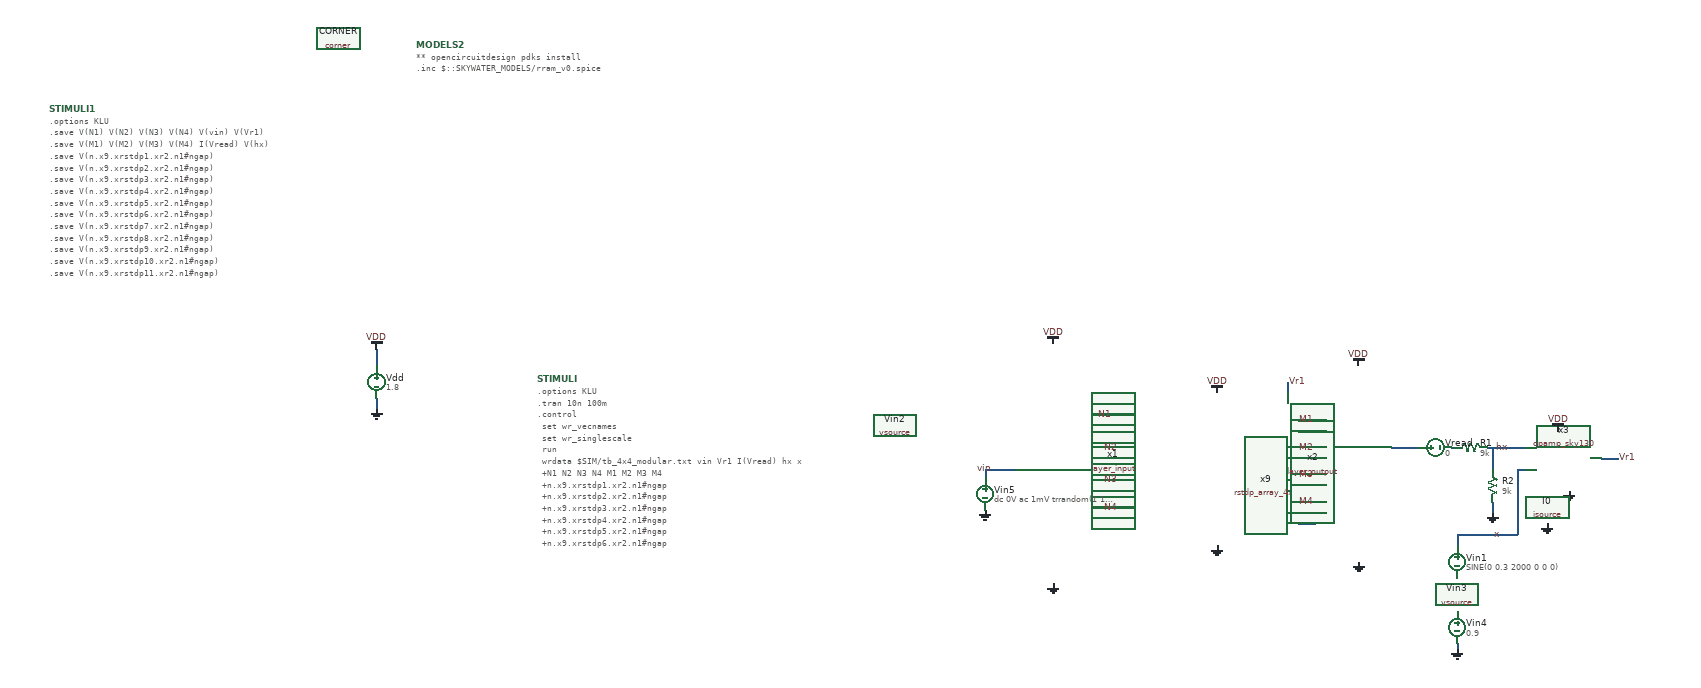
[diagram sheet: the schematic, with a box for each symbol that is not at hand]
v {xschem version=3.4.5 file_version=1.2
}
G {}
K {}
V {}
S {}
E {}
B 2 -840 -1020 -40 -620 {flags=graph
y1=1.2	
y2=6.8
ypos1=-0.00012
ypos2=3.7
divy=5
subdivy=1
unity=1
x1=0
x2=1e-06
divx=5
subdivx=1


dataset=-1
unitx=1
logx=0
logy=0
digital=0
linewidth_mult=3.5
color="6 8 4 7"
node="\\"N1; n1 1.8 3 * +\\"
\\"N2; n2 1.8 2 * +\\"
\\"N3; n3 1.8 +\\"
\\"N4; n4\\""}
B 2 -840 -1430 -40 -1030 {flags=graph
y1=1.3	
y2=1.5
ypos1=-0.319016
ypos2=2.49867
divy=5
subdivy=1
unity=1
x1=0
x2=1e-06
divx=5
subdivx=1


dataset=-1
unitx=1
logx=0
logy=0
digital=0
linewidth_mult=3.5
color=6
node=vin}
B 2 840 -1020 1640 -620 {flags=graph
y1=-0.005	
y2=7.3
ypos1=-0.00012
ypos2=3.7
divy=5
subdivy=1
unity=1
x1=0
x2=1e-06
divx=5
subdivx=1


dataset=-1
unitx=1
logx=0
logy=0
digital=0
linewidth_mult=3.5
color="6 8 4 7"
node="\\"N1; m1 5.4 +\\"
\\"N2; m2 3.6 +\\"
\\"N3; m3 1.8 +\\"
\\"N4; m4\\""}
B 2 0 -1015 800 -615 {flags=graph
y1=0.0028	
y2=1.9
ypos1=-0.00012
ypos2=3.7
divy=5
subdivy=1
unity=1
x1=0
x2=1e-06
divx=5
subdivx=1


dataset=-1
unitx=1
logx=0
logy=0
digital=0
linewidth_mult=3.5

color="4 5"
node="vr1
hx"}
B 2 0 -1430 800 -1030 {flags=graph
y1=1.6	
y2=4.6
ypos1=-0.00012
ypos2=3.7
divy=5
subdivy=1
unity=1
x1=0
x2=1e-06
divx=5
subdivx=1


dataset=-1
unitx=1
logx=0
logy=0
digital=0
linewidth_mult=3.5

color="4 5 6 7 8 9 10 11 12 13 14 15 16 17 18 19"
node="\\"Mem16; 5 n.x9.xrstdp16.xr2.n1#ngap - \\"
\\"Mem15; 5 n.x9.xrstdp15.xr2.n1#ngap - \\"
\\"Mem14; 5 n.x9.xrstdp14.xr2.n1#ngap - \\"
\\"Mem13; 5 n.x9.xrstdp13.xr2.n1#ngap - \\"
\\"Mem12; 5 n.x9.xrstdp12.xr2.n1#ngap - \\"
\\"Mem11; 5 n.x9.xrstdp11.xr2.n1#ngap - \\"
\\"Mem10; 5 n.x9.xrstdp10.xr2.n1#ngap - \\"
\\"Mem9; 5 n.x9.xrstdp9.xr2.n1#ngap - \\"
\\"Mem8; 5 n.x9.xrstdp8.xr2.n1#ngap - \\"
\\"Mem7; 5 n.x9.xrstdp7.xr2.n1#ngap - \\"
\\"Mem6; 5 n.x9.xrstdp6.xr2.n1#ngap - \\"
\\"Mem5; 5 n.x9.xrstdp5.xr2.n1#ngap - \\"
\\"Mem4; 5 n.x9.xrstdp4.xr2.n1#ngap - \\"
\\"Mem3; 5 n.x9.xrstdp3.xr2.n1#ngap - \\"
\\"Mem2; 5 n.x9.xrstdp2.xr2.n1#ngap - \\"
\\"Mem1; 5 n.x9.xrstdp1.xr2.n1#ngap - \\""}
B 2 840 -1430 1640 -1030 {flags=graph
y1=7.5e-07	
y2=4.3e-05
ypos1=-0.00012
ypos2=3.7
divy=5
subdivy=1
unity=1
x1=0
x2=1e-06
divx=5
subdivx=1


dataset=-1
unitx=1
logx=0
logy=0
digital=0
linewidth_mult=3.5

color=4
node=i(Vread)}
N -1120 -520 -1120 -490 {
lab=VDD}
N -1120 -430 -1120 -410 {
lab=GND}
N 860 -180 860 -160 {
lab=x}
N 860 -180 970 -180 {
lab=x}
N 240 -400 270 -400 {
lab=N1}
N 240 -230 270 -230 {
lab=N4}
N 740 -340 790 -340 {
lab=#net1}
N 220 -400 240 -400 {
lab=N1}
N 190 -250 220 -250 {
lab=N4}
N 220 -230 240 -230 {
lab=N4}
N 230 -340 270 -340 {
lab=N2}
N 190 -310 230 -310 {
lab=N3}
N 230 -300 230 -280 {
lab=N3}
N 230 -280 270 -280 {
lab=N3}
N 570 -340 620 -340 {
lab=M2}
N 570 -320 620 -320 {
lab=#net2}
N 570 -280 590 -280 {
lab=M3}
N 590 -290 590 -280 {
lab=M3}
N 590 -290 620 -290 {
lab=M3}
N 600 -270 620 -270 {
lab=#net3}
N 600 -270 600 -260 {
lab=#net3}
N 570 -260 600 -260 {
lab=#net3}
N 570 -220 580 -220 {
lab=M4}
N 580 -240 580 -220 {
lab=M4}
N 580 -240 620 -240 {
lab=M4}
N 570 -200 600 -200 {
lab=#net4}
N 600 -220 600 -200 {
lab=#net4}
N 600 -220 620 -220 {
lab=#net4}
N 570 -370 620 -370 {
lab=#net5}
N 570 -390 620 -390 {
lab=M1}
N 220 -420 220 -400 {
lab=N1}
N 190 -420 220 -420 {
lab=N1}
N 230 -370 230 -340 {
lab=N2}
N 190 -370 230 -370 {
lab=N2}
N 230 -310 230 -300 {
lab=N3}
N 220 -250 220 -230 {
lab=N4}
N 915 -340 945 -340 {
lab=hx}
N 955 -340 985 -340 {
lab=hx}
N 945 -340 955 -340 {
lab=hx}
N 925 -240 925 -220 {
lab=GND}
N 925 -340 925 -300 {
lab=hx}
N 1125 -320 1155 -320 {
lab=Vr1}
N 550 -460 550 -440 {
lab=Vr1}
N 850 -340 855 -340 {
lab=#net6}
N 190 -400 270 -380 {
lab=#net7}
N 190 -350 270 -320 {
lab=#net8}
N 190 -290 270 -260 {
lab=#net9}
N 190 -230 270 -210 {
lab=#net10}
N 860 20 860 30 {
lab=GND}
N 970 -300 970 -255 {
lab=x}
N 970 -300 985 -300 {
lab=x}
N 970 -255 970 -180 {
lab=x}
N -5 -300 -5 -285 {
lab=vin}
N -5 -300 50 -300 {
lab=vin}
C {devices/vsource.sym} -1120 -460 0 0 {name=Vdd value=1.8}
C {devices/gnd.sym} -1120 -410 0 0 {name=l5 lab=GND}
C {sky130_fd_pr/corner.sym} -1190 -1090 0 0 {name=CORNER only_toplevel=true corner=tt}
C {devices/code_shown.sym} -825 -465 0 0 {name=STIMULI 
only_toplevel=true
place=end
value="


.options KLU
.tran 10n 100m
.control
	set wr_vecnames
	set wr_singlescale
	run
	wrdata $SIM/tb_4x4_modular.txt vin Vr1 I(Vread) hx x
	+N1 N2 N3 N4 M1 M2 M3 M4  
	+n.x9.xrstdp1.xr2.n1#ngap 
	+n.x9.xrstdp2.xr2.n1#ngap 
	+n.x9.xrstdp3.xr2.n1#ngap
	+n.x9.xrstdp4.xr2.n1#ngap 
	+n.x9.xrstdp5.xr2.n1#ngap 
	+n.x9.xrstdp6.xr2.n1#ngap
	+n.x9.xrstdp7.xr2.n1#ngap 
	+n.x9.xrstdp8.xr2.n1#ngap 
	+n.x9.xrstdp9.xr2.n1#ngap
	+n.x9.xrstdp10.xr2.n1#ngap 
	+n.x9.xrstdp11.xr2.n1#ngap 
	+n.x9.xrstdp12.xr2.n1#ngap
	+n.x9.xrstdp13.xr2.n1#ngap 
	+n.x9.xrstdp14.xr2.n1#ngap 
	+n.x9.xrstdp15.xr2.n1#ngap
.endc
"}
C {devices/vdd.sym} -1120 -520 0 0 {nname=l4 lab=VDD}
C {devices/launcher.sym} -1095 -665 0 0 {name=h5
descr="load waves" 
tclcommand="xschem raw_read $netlist_dir/tb_4x4_modular.raw tran"
q}
C {devices/gnd.sym} 860 30 0 0 {name=l18 lab=GND}
C {Synapse/rstdp_array_4x4.sym} 420 -230 0 0 {name=x9}
C {devices/gnd.sym} 420 -160 0 0 {name=l30 lab=GND}
C {devices/vdd.sym} 420 -440 0 0 {name=l31 lab=VDD}
C {devices/code.sym} -1047.5 -1077.5 0 0 {name=MODELS2
only_toplevel=true
format="tcleval( @value )"
value="
** opencircuitdesign pdks install
.inc $::SKYWATER_MODELS/rram_v0.spice
"
spice_ignore=false}
C {layer/layer_input.sym} 130 -250 0 0 {name=x1}
C {layer/layer_output.sym} 770 -340 0 0 {name=x2}
C {devices/vdd.sym} 680 -490 0 0 {name=l6 lab=VDD}
C {devices/gnd.sym} 680 -130 0 0 {name=l7 lab=GND}
C {devices/gnd.sym} 120 -90 0 0 {name=l8 lab=GND}
C {devices/lab_pin.sym} 230 -400 1 0 {name=p2 sig_type=std_logic lab=N1}
C {devices/lab_pin.sym} 240 -340 1 0 {name=p3 sig_type=std_logic lab=N2}
C {devices/lab_pin.sym} 240 -280 1 0 {name=p4 sig_type=std_logic lab=N3}
C {devices/lab_pin.sym} 240 -230 1 0 {name=p5 sig_type=std_logic lab=N4}
C {devices/lab_pin.sym} 600 -390 1 0 {name=p6 sig_type=std_logic lab=M1}
C {devices/lab_pin.sym} 600 -340 1 0 {name=p7 sig_type=std_logic lab=M2}
C {devices/lab_pin.sym} 600 -290 1 0 {name=p8 sig_type=std_logic lab=M3}
C {devices/lab_pin.sym} 600 -240 1 0 {name=p9 sig_type=std_logic lab=M4}
C {devices/vdd.sym} 120 -530 0 0 {name=l9 lab=VDD}
C {OPAMP/opamp_sky130.sym} 1055 -320 0 0 {name=x3}
C {devices/lab_pin.sym} 955 -340 1 1 {name=p10 sig_type=std_logic lab=hx}
C {devices/res.sym} 885 -340 3 0 {name=R1
value=9k
footprint=1206
device=resistor
m=1}
C {devices/res.sym} 925 -270 0 0 {name=R2
value=9k
footprint=1206
device=resistor
m=1}
C {devices/gnd.sym} 925 -220 0 0 {name=l16 lab=GND}
C {devices/gnd.sym} 1065 -260 0 0 {name=l10 lab=GND}
C {devices/vdd.sym} 1045 -370 0 0 {name=l19 lab=VDD}
C {devices/lab_pin.sym} 940 -180 1 1 {name=p12 sig_type=std_logic lab=x
}
C {devices/lab_pin.sym} 1155 -320 2 0 {name=p11 sig_type=std_logic lab=Vr1
}
C {devices/isource.sym} 1025 -230 0 0 {name=I0 value=100u}
C {devices/gnd.sym} 1025 -200 0 0 {name=l13 lab=GND}
C {devices/vsource.sym} 860 -130 0 1 {name=Vin1 value="SINE(0 0.3 2000 0 0 0)"
spice_ignore=false}
C {devices/vsource.sym} 820 -340 3 1 {name=Vread value=0
spice_ignore=false}
C {devices/vsource.sym} -170 -380 0 1 {name=Vin2 value="PWL(0 0.9 250u 1.8 750u 0 1000u 0.9)"
spice_ignore=true}
C {devices/vsource.sym} 860 -70 0 1 {name=Vin3 value="SINE(0 0.5 5000 0 0 90)"
spice_ignore=false}
C {devices/vsource.sym} 860 -10 0 1 {name=Vin4 value=0.9
spice_ignore=false}
C {devices/code_shown.sym} -1720 -960 0 0 {name=STIMULI1 
only_toplevel=true
place=end
value="
.options KLU
.save V(N1) V(N2) V(N3) V(N4) V(vin) V(Vr1)
.save V(M1) V(M2) V(M3) V(M4) I(Vread) V(hx)
.save V(n.x9.xrstdp1.xr2.n1#ngap)
.save V(n.x9.xrstdp2.xr2.n1#ngap)
.save V(n.x9.xrstdp3.xr2.n1#ngap)
.save V(n.x9.xrstdp4.xr2.n1#ngap)
.save V(n.x9.xrstdp5.xr2.n1#ngap)
.save V(n.x9.xrstdp6.xr2.n1#ngap)
.save V(n.x9.xrstdp7.xr2.n1#ngap)
.save V(n.x9.xrstdp8.xr2.n1#ngap)
.save V(n.x9.xrstdp9.xr2.n1#ngap)
.save V(n.x9.xrstdp10.xr2.n1#ngap)
.save V(n.x9.xrstdp11.xr2.n1#ngap)
.save V(n.x9.xrstdp12.xr2.n1#ngap)
.save V(n.x9.xrstdp13.xr2.n1#ngap)
.save V(n.x9.xrstdp14.xr2.n1#ngap)
.save V(n.x9.xrstdp15.xr2.n1#ngap)
.tran 20n 5u
.control
	set wr_vecnames
	set wr_singlescale
	run
	write tb_4x4_modular.raw
.endc
"
spice_ignore=true}
C {devices/lab_pin.sym} 550 -460 2 0 {name=p13 sig_type=std_logic lab=Vr1
}
C {devices/gnd.sym} -5 -225 0 0 {name=l1 lab=GND}
C {devices/lab_pin.sym} 10 -300 3 1 {name=p1 sig_type=std_logic lab=vin
}
C {devices/vsource.sym} -5 -255 0 1 {name=Vin5 value="dc 0V ac 1mV trrandom(1 1u 0s 0.9 0.6) "
spice_ignore=false}
